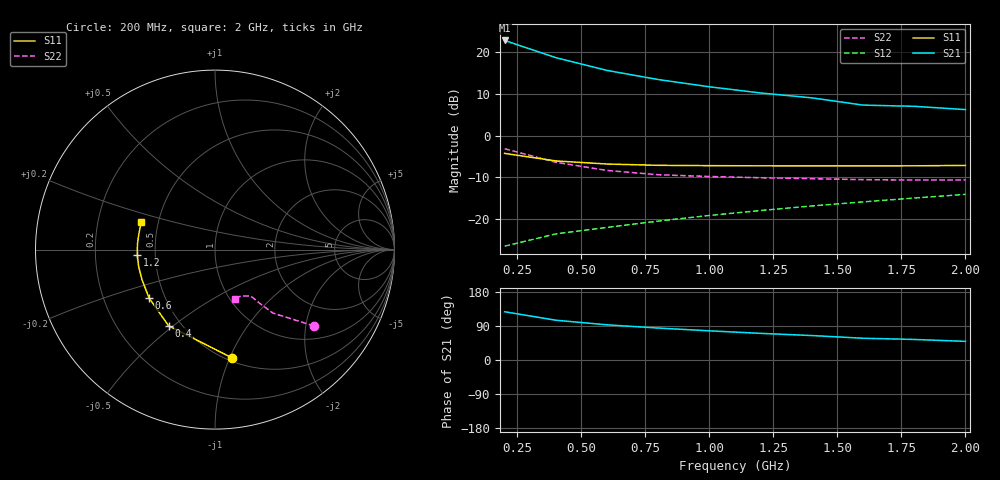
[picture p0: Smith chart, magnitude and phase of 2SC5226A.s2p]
# MHz S ma R 50
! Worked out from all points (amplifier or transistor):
!   10 points, 200 MHz to 2 GHz, reference 50 ohm
!   highest |S21| = 22.9 dB at 200 MHz (marker M1)
!   |S21| within 3 dB of that: start of sweep to 345.3 MHz
!   unconditionally stable (mu >= 1): 1.459 GHz to 1.828 GHz
!   at 400 MHz: K = 0.60, MSG = 21.2 dB, |S12| = -23.6 dB
!   at 1.2 GHz: K = 0.96, MSG = 14.1 dB, |S12| = -18.0 dB
!   at 2 GHz: K = 0.99, MSG = 10.2 dB, |S12| = -14.1 dB
!   S11 on the Smith chart (normalised r, x): 200 MHz: 0.53, -1.02; 400 MHz: 0.43, -0.48; 600 MHz: 0.41, -0.28; 1.2 GHz: 0.40, -0.03; 2 GHz: 0.40, +0.15
200  0.612 -80.9  13.93 127.3  0.047 57.1  0.697 -37.6
400  0.497 -121.3  8.656 105.0  0.066 51.3  0.479 -47.6
600  0.456 -143.5  6.08 92.8  0.079 52.9  0.382 -50.5
800  0.44 -157.6  4.725 84.3  0.094 55.4  0.339 -51.8
1000  0.436 -167.5  3.864 77.0  0.11 56.8  0.323 -53.4
1200  0.434 -176.1  3.258 70.3  0.126 57.9  0.312 -55.8
1400  0.433 176.6  2.847 64.5  0.143 58.4  0.304 -58.3
1600  0.433 170.9  2.329 57.4  0.16 58.9  0.296 -62.0
1800  0.434 165.0  2.252 54.2  0.178 58.6  0.293 -65.0
2000  0.439 159.6  2.057 49.2  0.197 58.1  0.294 -68.1
